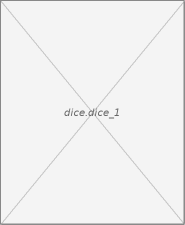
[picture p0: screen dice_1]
VISUALIZATION dice_1  // 185x225
    Image (0,0 185x225), image: dice.dice_1
END_VISUALIZATION
